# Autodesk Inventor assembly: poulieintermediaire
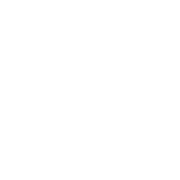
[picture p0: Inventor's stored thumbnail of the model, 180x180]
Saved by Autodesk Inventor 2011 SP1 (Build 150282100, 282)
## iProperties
Created: 2010-12
Part Number: poulieintermediaire
Document SubType Name: Assembly
Designer: eric
Author: eric
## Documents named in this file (10)
- D:\eduinventor\maquettesaip2011\machineàpain\Workspace\poulieintermediaire.iam
- D:\eduinventor\maquettesaip2011\machineàpain\Workspace\rondelle de frottement axe de poulie.ipt
- D:\eduinventor\maquettesaip2011\machineàpain\Workspace\poulie intermediaire.ipt
- D:\eduinventor\maquettesaip2011\machineàpain\Workspace\platine de poulie.ipt
- D:\eduinventor\maquettesaip2011\machineàpain\Workspace\accouplement d axe de poulie.ipt
- D:\eduinventor\maquettesaip2011\machineàpain\Workspace\segment d arret.ipt
- D:\eduinventor\maquettesaip2011\machineàpain\Workspace\rondelle  M5.ipt
- D:\eduinventor\maquettesaip2011\machineàpain\Workspace\Rondelle, W 5.ipt
- D:\eduinventor\maquettesaip2011\machineàpain\Workspace\Ecrou H FR, M 5.iam
- D:\eduinventor\maquettesaip2011\machineàpain\Workspace\axe de poulie.ipt
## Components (10 placed, 9 different names)
1. platine de poulie:1
2. poulie intermediaire:1
3. segment d arret:1
4. rondelle  M5:1
5. Rondelle, W 5:1
6. Ecrou H FR, M 5:1 [sub-assembly]
7. rondelle de frottement axe de poulie:1
8. accouplement d axe de poulie:1
9. axe de poulie:1
10. rondelle de frottement axe de poulie:2
